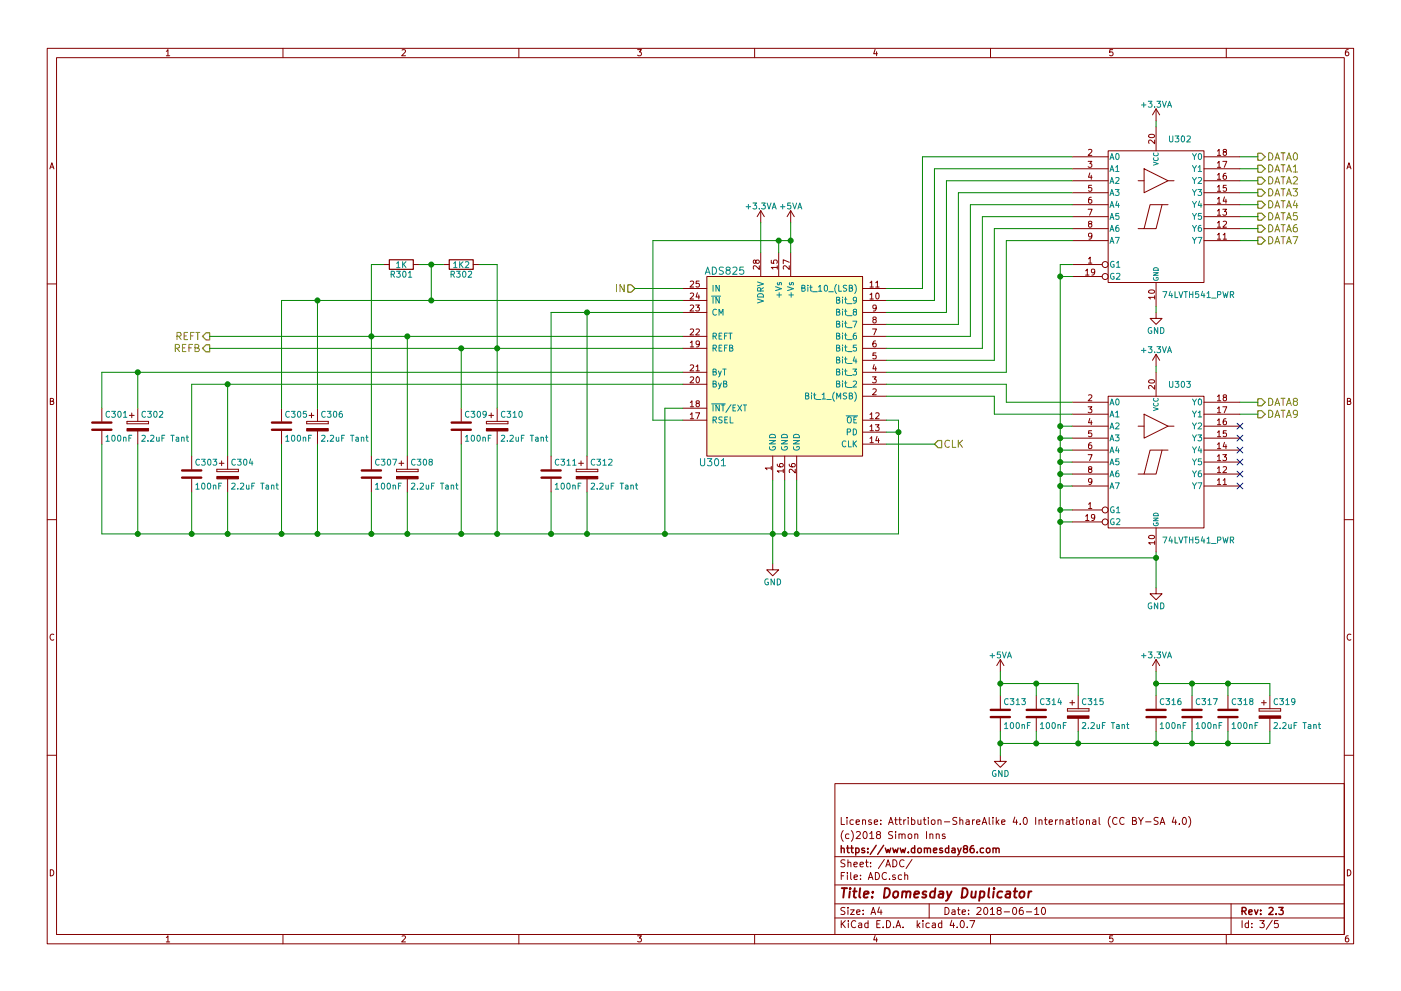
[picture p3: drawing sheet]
<svg xmlns="http://www.w3.org/2000/svg" width="297mm" height="210mm" viewBox="0 0 297 210" stroke-linecap="round" stroke-linejoin="round" font-family="sans-serif">
<g fill="none" stroke="#840000" stroke-width=".21">
<path d="M10 10.3h277v189.9h-277zM12 12.2h273v186.1h-273zM35.3 10.9l.3-.4v1.3M35.3 11.8h.7M60 10.3v1.9M85.2 10.6l.5-.1 .3 .4-.8 .9h.8M110 10.3v1.9M135.2 10.5h.8l-.4 .5 .3 .1 .1 .2-.1 .4-.2 .1-.5-.1M160 10.3v1.9M185.5 10.5l-.3 .9h.8M185.9 11v.8M210 10.3v1.9"/>
<path d="M235.9 10.5h-.6v.6h.6l.1 .5-.3 .2-.4-.1M260 10.3v1.9M285.9 10.5l-.4 .1-.2 .2-.1 .8 .3 .2 .4-.1 .1-.4-.1-.2-.4-.1-.3 .3M10.6 35.8l.4-1.3 .4 1.3M10.7 35.5h.6M227.3 38.3h7.6M227.3 33.3h7.6M227.3 35.8h7.6M230.7 34.2h.8l-.4 .5 .3 .1v.6l-.1 .1-.6-.1M230.8 31.8l.5-.1 .2 .3-.8 1h.8M231.1 36.7l-.3 .9h.7M231.4 37.2v.8"/>
<path d="M231.4 39.3h-.6v.6h.6v.6l-.1 .1-.5-.1M234.9 32h20.4v27.9h-20.4zM241.3 38.3h1.3M242.6 35.8l5 2.5-5 2.6zM243.6 28.7a.76 .76 0 0 1 1.2 .2 .74 .74 0 0 1-1.3-.1zM244.8 29.7v.8l-.9-.8-.4 .2 .1 .5M245.1 23.1v2.5M245.1 26.9v5.1M245.1 23.1l-.8 1.3M245.1 23.1l.8 1.3M247.6 38.3h1.3M255.3 38.3h7.6"/>
<path d="M255.3 33.3h7.6M255.3 35.8h7.6M258.1 39.7l.4-.4v1.3M258.1 37.1l.4-.3v1.2M258.1 34.6l.4-.4v1.3M258.1 32l.4-.3v1.3M258.1 38h.7M258.1 35.5h.7M258.1 33h.7M259.3 34.2h.8l-.5 1.3M259.6 32.2l-.3-.2 .1-.3 .6 .1v.3l-.6 .2-.1 .2 .1 .3 .2 .2h.2l.2-.3v-.3l-.2-.2M259.9 36.8h-.3l-.2 .3-.1 .7 .3 .2 .4-.1-.1-.6h-.3l-.3 .2"/>
<path d="M260 39.3h-.6l-.1 .6h.7v.6l-.2 .1-.5-.1M285.6 35.8l.4-1.3 .4 1.3M285.7 35.5h.6M81.3 56.1h1.2M87.6 56.1h1.3M94 56.1h1.2M100.3 56.1h1.3M146.4 59.7l.4-.1 .3 .4-.8 .9h.8M148.2 59.6h-.6v.6h.6v.6l-.1 .1-.5-.1M149.9 58.7h33v38.1h-33zM160.2 55.4l.3-.2h.4l.1 .2-.1 .4-.4 .1-.2-.1-.2-.6h-.3v.6l.2 .1 .2-.3M161 56.4v.8l-.9-.8-.4 .2 .1 .5"/>
<path d="M161.3 44.7v2.5M161.3 53.6v5.1M161.3 44.7l-.8 1.3M161.3 44.7l.8 1.3M163.5 55.2v.6l.6 .1v-.7h.6l.1 .2-.1 .5M164.8 56.7h-1.3l.4 .4M164.8 56.4v.7M165.1 53.6v5.1M167.3 56.4v.8l-.9-.8-.3 .2 .1 .5M167.3 55.6l-1.2-.5v.9M167.6 44.7v2.5M167.6 53.6v5.1"/>
<path d="M167.6 44.7l-.7 1.3M167.6 44.7l.8 1.3M184.5 60l.3-.4v1.3M185.7 60l.3-.4v1.3M227.3 56.1h6.4M227.3 40.9h7.6M227.3 43.4h7.6M227.3 46h7.6M227.3 48.5h7.6M227.3 51h7.6M227.3 58.7h6.4M230.2 57.4l.3-.3v1.3"/>
<path d="M230.2 58.4h.7M230.7 44.4h.8l-.5 1.3M230.8 54.9l.3-.3v1.2M230.8 55.8h.7M231 47.5l-.2-.3v-.2h.6v.3l-.5 .2-.1 .2v.4l.2 .1h.3l.2-.3-.1-.3-.1-.1M231.4 41.9h-.4l-.2 .3v.7l.2 .2 .4-.1v-.6l-.4-.1-.2 .3M231.5 50l-.2 .3-.4-.1-.1-.6 .5-.1 .2 .2-.1 .7-.3 .3h-.2M232.1 57.6l-.2 .3-.4-.1-.1-.6 .5-.1 .2 .2v.8l-.4 .3h-.2M245.1 59.9v5.1M246.4 43.4l-1.3 5.1h-2.5M247.6 43.4h-3.8l-1.2 5.1h-1.3M255.3 40.9h7.6"/>
<path d="M255.3 43.4h7.6M255.3 46h7.6M255.3 48.5h7.6M255.3 51h7.6M258.1 49.8l.4-.3v1.2M258.1 47.3l.4-.4v1.3M258.1 44.7l.4-.3v1.3M258.1 42.2l.4-.3v1.2M258.1 50.7h.7M258.1 48.2h.7M258.1 45.7h.7M258.1 43.1h.7"/>
<path d="M258.1 40.6h.7M259.3 44.4h.7l-.4 .5 .4 .1v.5l-.2 .2-.5-.2M259.3 49.8l.4-.3v1.2M259.3 47l.5-.1 .2 .4-.7 .9h.7M259.3 50.7h.7M259.6 41.8l-.3 .9h.8M259.9 42.3v.8M10 60.2h2M144.8 79h5.1M144.8 73.9h5.1M144.8 71.4h5.1M144.8 66.3h5.1"/>
<path d="M144.8 63.7h5.1M144.8 61.2h5.1M146.4 77.5l.4-.1 .3 .4-.8 .9h.8M146.4 69.9l.4-.1 .3 .3-.8 1h.8M146.4 64.8l.4-.1 .3 .4-.8 .9h.8M146.4 62.3l.4-.1 .3 .3-.8 .9h.8M146.4 72.7l.3-.4v1.3M146.4 73.6h.7M147.5 64.7h.8l-.4 .5 .3 .1v.6l-.1 .1-.6-.1M147.6 77.8l.3-.4v1.3M147.6 69.9l.5-.1 .2 .3-.8 1h.8M147.6 78.7h.7"/>
<path d="M147.9 62.1l-.3 .9h.7M148.2 62.6v.8M148.3 72.9l-.2 .2-.4-.1-.1-.6 .5-.1 .2 .3-.1 .7-.3 .3h-.2M182.9 79h5.1M182.9 76.4h5.1M182.9 73.9h5.1M182.9 71.4h5.1M182.9 68.8h5.1M182.9 66.3h5.1M182.9 63.7h5.1M182.9 61.2h5.1M184.5 62.5l.3-.3v1.2"/>
<path d="M184.5 63.4h.7M184.5 60.9h.7M185 80h.8l-.5 .4 .4 .1v.6l-.2 .1-.5-.1M185 69.8h.8l-.5 1.3M185.3 67.8l-.2-.2v-.2h.6v.3l-.5 .1-.1 .2v.4l.2 .1h.2l.3-.2-.1-.4-.2-.1M185.3 77.3l-.2 1h.7M185.6 72.3l-.3 .1-.2 .2v.7l.2 .3 .4-.1-.1-.6-.3-.1-.2 .2M185.6 77.8v.9M185.7 60.9h.7M185.7 74.9h-.6v.6h.6v.5l-.2 .1-.4-.1M185.8 65.2l-.3 .3-.3-.1-.1-.6 .4-.1 .3 .2-.1 .8-.3 .3h-.2M185.8 62.3l.2-.1a.67 .67 0 0 1 .4 .6 .67 .67 0 0 1-.4 .6l-.3-.4z"/>
<path d="M243.6 61.7a.76 .76 0 0 1 1.2 .2 .74 .74 0 0 1-1.3-.1zM244.8 63.1h-1.3l.4 .3M244.8 62.7v.7M245.1 66.3v1.3h1.3l-1.3 1.2-1.3-1.2h1.3M245.1 75.2v2.5M245.1 79v5.1M245.1 75.2l-.8 1.2M245.1 75.2l.8 1.2M285 60.2h2M10.7 85.1h.5l.1-.5-.6-.1v1.3h.5l.2-.4-.3-.3M21.6 86.6v2.8M21.6 91.4v2.8"/>
<path d="M26.9 89.4v.5zM26.9 89.9h4.6zM26.9 89.4h4.6zM27.4 88.1h1M27.9 87.6v1M29.2 86.6v2.8M29.2 91.4v2.8M31.5 89.4v.5zM40.6 96.8v2.8M46 99.6v.5zM46 99.6h4.5zM46.5 98.3h1"/>
<path d="M47 97.8v1M48.3 96.8v2.8M50.5 99.6v.5zM59.7 86.6v2.8M59.7 91.4v2.8M65 89.4v.5zM65 89.9h4.6zM65 89.4h4.6zM65.5 88.1h1M66 87.6v1M67.3 86.6v2.8M67.3 91.4v2.8"/>
<path d="M69.6 89.4v.5zM78.7 96.8v2.8M84.1 99.6v.5zM84.1 99.6h4.5zM84.6 98.3h1M85.1 97.8v1M86.4 96.8v2.8M88.6 99.6v.5zM97.8 86.6v2.8M97.8 91.4v2.8M103.1 89.4v.5zM103.1 89.9h4.6z"/>
<path d="M103.1 89.4h4.6zM103.6 88.1h1M104.1 87.6v1M105.4 86.6v2.8M105.4 91.4v2.8M107.7 89.4v.5zM116.8 96.8v2.8M122.2 99.6v.5zM122.2 99.6h4.5zM122.7 98.3h1M123.2 97.8v1M124.5 96.8v2.8"/>
<path d="M126.7 99.6v.5zM144.8 81.5h5.1M144.8 89.1h5.1M144.8 86.6h5.1M146.4 80.1l.4-.1 .3 .3-.8 .9h.8M146.4 87.9l.3-.3v1.2M146.4 85.4l.3-.4v1.3M146.4 88.8h.7M146.4 86.3h.7M147.5 87.6h.8l-.5 1.2M147.7 80.1l.2-.1a.67 .67 0 0 1 .4 .6 .67 .67 0 0 1-.4 .6l-.3-.5zM147.8 85.6l-.2-.3v-.2h.6v.3l-.5 .2-.1 .2v.4l.2 .1h.3l.2-.3-.1-.3-.1-.1"/>
<path d="M163.5 99.3h-1.2l.3 .4M163.5 99v.7M163.8 96.8v5M164.8 98.5v.3l.3 .2 .7 .1 .3-.3-.2-.4-.6 .1v.3l.2 .3M166.1 99.9h-1.3l.4 .4M166.1 99.6v.7M166.4 96.8v5M167.3 98.5l.1 .3 .2 .2 .8 .1 .2-.3-.1-.4-.6 .1-.1 .3 .2 .3M168.6 99.6v.7l-.9-.7-.4 .2 .1 .5M168.9 96.8v5M182.9 84.1h5.1M182.9 81.5h5.1"/>
<path d="M182.9 89.1h5.1M182.9 91.7h5.1M182.9 94.2h5.1M184.5 87.9l.3-.3v1.2M184.5 90.5l.3-.4v1.3M184.5 93l.3-.3v1.2M184.5 88.8h.7M184.5 91.4h.7M184.5 93.9h.7M185.1 82.6l.4-.1 .3 .3-.8 1h.8M185.6 90.1h.8l-.4 .5 .3 .1v.6l-.1 .1-.6-.1M185.7 87.7l.5-.1 .2 .3-.8 .9h.8"/>
<path d="M186 92.6l-.3 .9h.7M186.3 93.1v.8M227.3 90.4h7.6M227.3 85.3h7.6M227.3 87.9h7.6M227.3 93h7.6M227.3 95.5h7.6M227.3 98h7.6M230.7 86.3h.8l-.4 .5 .3 .1v.5l-.1 .2-.6-.2M230.7 96.5h.8l-.5 1.2M230.8 83.9l.5-.1 .2 .3-.8 .9h.8M231 99.5l-.2-.2v-.2h.6v.3l-.5 .2-.1 .2v.3l.2 .2h.3l.2-.3-.1-.3-.1-.2"/>
<path d="M231.1 88.8l-.3 .9h.7M231.4 93.9l-.4 .1-.2 .2v.7l.2 .3 .4-.1v-.6l-.4-.1-.2 .2M231.4 89.2v.9M231.4 91.4h-.6v.6h.6v.5l-.1 .2-.5-.2M234.9 84.1h20.4v27.9h-20.4zM241.3 90.4h1.3M242.6 87.9l5 2.5-5 2.6zM243.6 80.7a.76 .76 0 0 1 1.2 .3 .74 .74 0 0 1-1.3-.1zM244.8 81.8v.8l-.9-.8-.4 .2 .1 .5M246.4 95.5l-1.3 5.1h-2.5M247.6 95.5h-3.8l-1.2 5.1h-1.3M247.6 90.4h1.3"/>
<path d="M255.3 90.4h7.6M255.3 85.3h7.6M255.3 87.9h7.6M255.3 93h7.6M255.3 95.5h7.6M255.3 98h7.6M258.1 99.4l.4-.4v1.3M258.1 96.8l.4-.3v1.2M258.1 94.3l.4-.4v1.3M258.1 91.7l.4-.3v1.3M258.1 89.2l.4-.4v1.3M258.1 86.7l.4-.4v1.3"/>
<path d="M258.1 84.1l.4-.3v1.2M258.1 97.7h.7M258.1 95.2h.7M258.1 92.7h.7M258.1 90.1h.7M258.1 87.6h.7M258.1 85h.7M259.3 96.5h.7l-.4 .4 .4 .1v.6l-.2 .1-.5-.1M259.3 86.3h.8l-.5 1.3M259.3 99.1l.5-.1 .2 .4-.7 .9h.7M259.6 84.3l-.3-.2 .1-.3 .6 .1v.3l-.6 .1-.1 .3 .1 .3 .2 .1h.2l.2-.2v-.4l-.2-.1M259.6 93.8l-.3 1h.8"/>
<path d="M259.9 88.8l-.3 .1-.2 .2-.1 .8 .3 .2 .4-.1-.1-.6-.3-.1-.3 .3M259.9 94.3v.9M260 91.4h-.6l-.1 .6h.7v.5l-.2 .2-.5-.2M285.7 85.1h.5l.1-.5-.6-.1v1.3h.5l.2-.4-.3-.3M10 110.3h2M40.6 101.6v2.8M46 100.1h4.5zM48.3 101.6v2.8M78.7 101.6v2.8M84.1 100.1h4.5zM86.4 101.6v2.8M116.8 101.6v2.8"/>
<path d="M122.2 100.1h4.5zM124.5 101.6v2.8M163.8 119.6v1.3h1.3l-1.3 1.3-1.2-1.3h1.2M227.3 108.2h6.4M227.3 100.6h7.6M227.3 103.1h7.6M227.3 110.7h6.4M230.2 109.5l.3-.3v1.2M230.2 110.4h.7M230.8 107l.3-.4v1.3M230.8 107.9h.7M231.5 102.1l-.2 .2h-.4l-.1-.7 .5-.1 .2 .3-.1 .7-.3 .3h-.2"/>
<path d="M232.1 109.7l-.2 .3-.4-.1-.1-.6 .5-.1 .2 .2v.7l-.4 .3h-.2M243.6 113.8a.76 .76 0 0 1 1.2 .2 .74 .74 0 0 1-1.3-.1zM244.8 115.2h-1.3l.4 .3M244.8 114.8v.7M245.1 112v5.1M255.3 100.6h7.6M255.3 103.1h7.6M258.1 101.9l.4-.4v1.3M258.1 102.8h.7M258.1 100.3h.7M259.3 101.9l.4-.4v1.3M259.3 102.8h.7"/>
<path d="M285 110.3h2M11.4 134.6a.58 .58 0 0 0-.8 .6 .58 .58 0 0 0 .8 .5M212.1 139.9v2.6M212.1 139.9l-.8 1.3M212.1 139.9l.8 1.3M245.1 124.7v1.3h1.3l-1.3 1.2-1.3-1.2h1.3M245.1 139.9v2.6M245.1 139.9l-.8 1.3M245.1 139.9l.8 1.3M286.4 134.6a.58 .58 0 0 0-.8 .6 .58 .58 0 0 0 .8 .5M212.1 147.6v2.8M212.1 152.4v2.8"/>
<path d="M219.7 147.6v2.8M219.7 152.4v2.8M226.3 150.4v.5zM226.3 150.9h4.6zM226.3 150.4h4.6zM226.8 149.1h1M227.3 148.6v1M228.6 147.6v2.8M228.6 152.4v2.8M230.9 150.4v.5zM245.1 147.6v2.8M245.1 152.4v2.8"/>
<path d="M252.7 147.6v2.8M252.7 152.4v2.8M260.3 147.6v2.8M260.3 152.4v2.8M267 150.4v.5zM267 150.9h4.5zM267 150.4h4.5zM267.5 149.1h1M268 148.6v1M269.2 147.6v2.8M269.2 152.4v2.8M271.5 150.4v.5z"/>
<path d="M10 160.2h2M177 166.3h108v32h-108zM178.4 173.4v1.5h.7M178.8 176.2a1.71 1.71 0 0 0 0 2.3M179.6 173.4v.2M179.6 173.9v1M180 177l-.4-.1-.3 .3v.6l.3 .1 .4-.1M180.5 176.2a1.71 1.71 0 0 1 0 2.3M180.9 174l-.4-.1-.3 .3 .1 .6 .2 .1 .4-.1M181.5 174.4l.7-.1v-.3l-.5-.1-.2 .2 .1 .7h.6M181.6 176.6l.5-.2 .3 .5-.9 1h.9M182.9 174.1l.2-.2 .4 .1v.9"/>
<path d="M182.9 173.9v1M183.1 176.6l.2-.2a.8 .8 0 0 1 .6 .8 .8 .8 0 0 1-.6 .7l-.3-.5zM184.4 176.9l.4-.5v1.5M184.4 177.9h.9M184.7 174l-.3-.1-.3 .2 .1 .3 .5 .1v.3h-.6M185.4 174.4l.7-.1-.1-.3-.4-.1-.2 .2v.7h.6M186.1 177.1l-.3-.3 .1-.2 .2-.2 .4 .1 .2 .2-.1 .2-.5 .2-.3 .3v.2l.3 .3h.3l.3-.3v-.2l-.3-.3M186.7 174.8v.1M186.7 174v.1M188.4 174.9l.5-1.5 .5 1.5M188.5 174.5h.7M189.3 176.5l-.6-.1-.3 .3 .1 .3 .7 .4v.4l-.2 .1-.6-.1"/>
<path d="M189.7 173.9h.5M189.9 176.4v.2M189.9 173.4v1.3l.3 .2M189.9 176.9v1M190.6 173.9h.5M190.6 177.1l.2-.2 .4 .1v.9M190.6 176.9v1M190.8 173.4v1.3l.3 .2M191.2 177.1l.3-.2 .3 .1 .1 .9M191.6 173.9v1M192 173.9l-.4 .3M192.6 173.4v.2"/>
<path d="M192.6 173.9v1M192.6 177.1l.2-.2 .4 .2 .1 .5-.1 .2-.4 .1-.2-.1zM193.3 174l.4-.1 .3 .3-.1 .6h-.6M193.3 173.4v1.5M194 177.1l.2-.2 .3 .1 .1 .9M194 176.9v1M194.6 173.9l.1 .9 .3 .1 .2-.1M195.2 173.9v1M195.8 173.9h.5M196 173.4v1.3l.3 .2M196.4 176.4v1.5M196.8 173.4v.2"/>
<path d="M196.8 173.9v1M197.2 177.1l.2-.2 .3 .1 .1 .9M197.2 176.9v1M197.5 174.1l.2-.2 .5 .2v.5l-.1 .2-.4 .1-.2-.1zM198.5 177.1l.2-.2 .4 .1v.9M198.5 176.9v1M198.9 174.1l.2-.2 .4 .1v.9M198.9 173.9v1M200.2 174.4h1.2M200.4 177l-.4-.1-.2 .2v.3l.6 .1v.3h-.6M202.9 173.5l-.6-.1-.3 .3 .1 .3 .7 .4v.4l-.2 .1-.6-.1M203.5 174.1l.2-.2 .4 .1v.9"/>
<path d="M203.5 173.4v1.5M204.9 174h.5l.1 .9M205.5 174.3l-.7 .3 .2 .3 .5-.1M206.2 173.9v1M206.6 173.9l-.4 .3M207.1 174.4l.7-.1-.1-.3-.4-.1-.2 .2v.7h.6M208.2 174.9l.5-1.5 .5 1.5M208.4 174.5h.7M209.7 173.4v1.3l.2 .2M210.5 173.4v.2M210.5 173.9v1M211.2 173.4v1.5"/>
<path d="M211.4 174.4l.4 .5M211.8 173.9l-.6 .6M212.1 160.3v1.2h1.3l-1.3 1.3-1.3-1.3h1.3M212.4 174.4l.7-.1-.1-.3-.4-.1-.2 .2v.7h.6M215.2 173.3l-.4 1.1h.9M215.5 173.9v1M216.3 174.8v.1M217.1 173.6l.2-.2a.8 .8 0 0 1 .5 .8 .8 .8 0 0 1-.5 .7l-.4-.5zM219.6 173.4v1.5M220.3 174.1l.2-.2 .4 .1v.9M220.3 173.9v1M221.4 173.9h.6"/>
<path d="M221.6 173.4v1.3l.4 .2M222.4 174.4l.7-.1v-.3l-.4-.1-.3 .2 .1 .7h.6M223.8 173.9v1M224.2 173.9l-.4 .3M224.7 174.1l.2-.2 .4 .1 .1 .9M224.7 173.9v1M226.1 174h.6v.9M226.7 174.3l-.7 .3 .2 .3 .5-.1M227.2 173.9h.6M227.4 173.4v1.3l.4 .2M228.3 173.4v.2M228.3 173.9v1"/>
<path d="M229 174.1l.2-.2 .4 .2 .1 .5-.1 .2-.4 .1-.2-.1zM230.4 174.1l.2-.2 .3 .1 .1 .9M230.4 173.9v1M231.7 174h.6v.9M232.3 174.3l-.7 .3 .3 .3 .4-.1M233 173.4v1.3l.2 .2M235.4 173.2a1.71 1.71 0 0 0 0 2.3M236.8 173.6a.71 .71 0 0 0-1 .5 .71 .71 0 0 0 .8 .8l.2-.1M238.3 173.6a.71 .71 0 0 0-1 .5 .71 .71 0 0 0 .7 .8l.3-.1M240.1 174.1l.7-.1v-.4l-.2-.2h-.5v1.5h.6l.2-.1 .1-.4-.4-.3M241.4 173.4l.5 .8 .5-.8M241.9 174.2v.7"/>
<path d="M242.9 174.4h1.1M245.5 173.5l-.5-.1-.3 .3 .1 .3 .7 .4v.4l-.2 .1-.6-.1M246 174.9l.5-1.5 .5 1.5M246.1 174.5h.7M248.9 173.3l-.4 1.1h1M249.3 173.9v1M250 174.8v.1M250.8 173.6l.2-.2a.8 .8 0 0 1 .6 .8 .8 .8 0 0 1-.6 .7l-.3-.5zM252 173.2a1.71 1.71 0 0 1 0 2.3M285 160.2h2M10.7 184.5a.65 .65 0 0 1 .7 .7 .65 .65 0 0 1-.7 .6zM35.3 198.9l.3-.4v1.3"/>
<path d="M35.3 199.8h.7M60 198.3v1.9M85.2 198.6l.5-.1 .3 .4-.8 .9h.8M110 198.3v1.9M135.2 198.5h.8l-.4 .5 .3 .1 .1 .2-.1 .4-.2 .1-.5-.1M160 198.3v1.9M177 194.8h108M177 191.8h108M177 187.8h108M177 181.8h108M178.4 195.3v1.5M178.4 185.8h.5"/>
<path d="M178.6 196l.6 .8M179.1 185.1h-.7v1.5M179.1 192.6l-.5-.1-.3 .3 .1 .3 .7 .4v.4l-.2 .1-.6-.1M179.1 182.5l-.5-.1-.3 .3 .1 .3 .7 .4v.4l-.2 .1-.6-.1M179.2 195.3l-.8 .9M179.7 185.1v.2M179.7 185.6v1M179.8 192.5v.2M179.8 183.1l.2-.2 .4 .1v.9M179.8 182.4v1.5M179.8 193v1M179.9 195.3v.2"/>
<path d="M179.9 195.8v1M180.3 193h.8l-.8 1h.8M180.4 185.1v1.3l.2 .2M181.1 183.4l.7-.1-.1-.3-.4-.1-.2 .2v.7h.6M181.1 186.1l.7-.1-.1-.3-.4-.1-.2 .2 .1 .7h.5M181.4 195.5a.71 .71 0 0 0-1 .5 .71 .71 0 0 0 .8 .8l.2-.1M181.6 193.5l.7-.1v-.3l-.4-.1-.3 .2 .1 .7h.6M182.1 195.9h.6v.9M182.3 183.4l.8-.1-.1-.3-.4-.1-.3 .2 .1 .7h.6M182.4 186.5v.1M182.4 185.7v.1M182.7 196.2l-.7 .3 .2 .3 .5-.1"/>
<path d="M183 193.9v.1M183 193.1v.1M183.5 182.9h.6M183.7 182.4v1.3l.4 .2M184 195.9l-.4-.1-.3 .3 .1 .6 .2 .1 .4-.1M184 195.3v1.5M184.1 186.6l.5-1.5 .5 1.5M184.2 186.2h.7M184.6 183.8v.1M184.6 183v.1M184.7 194l.4-1.5 .5 1.5M184.8 193.6h.7"/>
<path d="M185.5 198.5l-.3 .9h.8M185.6 185.1a.76 .76 0 0 1 .9 .8 .76 .76 0 0 1-.9 .7zM185.9 199v.8M185.9 196h.5M186.4 192.5l-.3 1h.9M186.6 195.3h-.7v1.5h.7M186.8 193v1M187.2 196.7v.1M187.5 182.3l-1.3 2M187.8 183.9l.5-1.5 .5 1.5M187.9 183.5h.7M188 195.3a.76 .76 0 0 1 .8 .8 .76 .76 0 0 1-.8 .7z"/>
<path d="M188 185.3a.71 .71 0 0 0-1 .5 .71 .71 0 0 0 .7 .8l.3-.1M188.6 186.5v.1M189.3 182.4a.76 .76 0 0 1 .9 .8 .76 .76 0 0 1-.9 .7zM189.5 196.7v.1M189.8 185.7l-.3-.1-.3 .2 .1 .2 .5 .2v.3h-.6M190 196.8l.4-1.5 .6 1.5M190.1 196.4h.7M191.2 185.7l-.5-.1-.3 .3 .1 .6 .2 .1 .5-.1M191.5 196.7v.1M191.7 182.6a.71 .71 0 0 0-1 .5 .71 .71 0 0 0 .7 .8l.3-.1M191.8 185.7l.2-.1 .4 .1 .1 .9M191.8 185.1v1.5"/>
<path d="M193.4 182.3l-1.3 2M194.5 195.3v1.5M194.6 196.3l.4 .5M195 195.8l-.5 .6M195.7 195.3v.2M195.7 195.8v1M197 191.8v3M197 195.9l-.4-.1-.3 .3 .1 .6 .2 .1 .4-.1M197.7 195.9h.6v.9M198.3 196.2l-.7 .3 .2 .3 .5-.1M199.7 195.9l-.5-.1-.2 .3v.6l.2 .1 .5-.1M199.7 195.3v1.5"/>
<path d="M200.4 192.5a.76 .76 0 0 1 .8 .8 .76 .76 0 0 1-.8 .7zM201.8 195.2l-.4 1.1h1M201.9 193.1h.5l.1 .9M202.2 195.8v1M202.5 193.4l-.7 .3 .2 .3 .5-.1M202.9 196.7v.1M203 193h.6M203.2 192.5v1.3l.4 .2M203.8 195.4l.1-.1a.8 .8 0 0 1 .6 .8 .8 .8 0 0 1-.6 .7 .97 .97 0 0 1-.1-1.4zM204 193.5l.7-.1-.1-.3-.4-.1-.2 .2 .1 .7h.5M205.1 196.7v.1M205.4 193.9v.1"/>
<path d="M205.4 193.1v.1M205.6 195.3h1.1l-.7 1.5M207.1 192.7l.6-.2 .3 .5-.9 1h.9M208.7 192.7l.2-.2a.8 .8 0 0 1 .5 .8 .8 .8 0 0 1-.5 .7l-.3-.5zM210 193l.4-.5v1.5M210 194h.8M210 198.3v1.9M211.7 193.2l-.3-.3 .1-.2 .2-.2 .4 .1 .2 .2-.1 .2-.5 .2-.3 .3v.2l.3 .3h.3l.3-.3v-.2l-.3-.3M212.9 193.5h1.1M214.8 192.7l.2-.2a.8 .8 0 0 1 .6 .8 .8 .8 0 0 1-.6 .7l-.3-.5zM216.8 192.5l-.4 .1a1.11 1.11 0 0 0-.1 1.3l.4 .1 .2-.1 .1-.5-.3-.3-.4 .1-.2 .2M217.6 193.5h1.1"/>
<path d="M219.4 193l.4-.5v1.5M219.4 194h.8M221 192.7l.2-.2a.8 .8 0 0 1 .5 .8 .8 .8 0 0 1-.5 .7l-.4-.5zM235.9 198.5h-.6v.7l.6-.1 .1 .5-.3 .2-.4-.1M260 198.3v1.9M261 191.8v6.5M263.3 195.3v1.5M264.7 195.9l-.4-.1-.3 .3 .1 .6 .2 .1 .4-.1M264.7 195.3v1.5M265.4 196.7v.1M265.4 195.9v.1M267.1 195.3h.9l-.5 .6 .5 .1v.7l-.2 .1-.7-.1"/>
<path d="M269.7 195.2l-1.2 2M271 195.3h-.7l-.1 .7h.7l.1 .2v.5l-.2 .1-.6-.1M285.7 184.5a.65 .65 0 0 1 .7 .7 .65 .65 0 0 1-.7 .6zM285.9 198.5l-.4 .1-.2 .3-.1 .7 .3 .2 .4-.1 .1-.4-.1-.2-.4-.1-.3 .3"/>
<circle cx="234.3" cy="58.7" r=".63"/>
<circle cx="234.3" cy="56.1" r=".63"/>
<circle cx="234.3" cy="108.2" r=".63"/>
<circle cx="234.3" cy="110.7" r=".63"/>
</g>
<g fill="none" stroke="#840000" stroke-width=".3">
<path d="M178.4 179.4v1.5M179.5 179.9h.6M179.7 179.4v1.3l.4 .2M180.4 179.9h.5M180.6 179.4v1.3l.3 .2M181.4 179.9v1.5M185.8 179.3l-1.3 2M187.4 179.3l-1.3 2M187.7 179.9l.3 1 .3-.7 .3 .7 .2-1M189.3 179.9l.3 1 .3-.7 .2 .7 .3-1M190.9 179.9l.3 1 .2-.7 .3 .7 .3-1M193.9 179.4v1.5"/>
<path d="M196 179.9v1M201.1 179.4v1.5M203 179.9l.4 1M203.8 179.9l-.5 1.4-.3 .1M206.4 179.4l-.4 .1a1.11 1.11 0 0 0-.2 1.3l.5 .1 .2-.1 .1-.5-.3-.3-.5 .1-.1 .2M210.5 179.9v1M178.4 180.1l.2-.2 .3 .1 .1 .9M181.4 180l.5-.1 .2 .3-.1 .6h-.6M183.3 180l-.4-.1-.2 .2 .1 .3 .5 .1v.3h-.6M184 180.8v.1M184 180v.1M192.6 180.8v.1"/>
<path d="M193.9 180l-.4-.1-.3 .3 .1 .6 .2 .1 .4-.1M194.6 180.1l.2-.2 .5 .2 .1 .5-.2 .2-.4 .1-.2-.1zM196 180.1l.2-.2 .4 .1v.9M196.6 180.1l.2-.2 .4 .1 .1 .9M197.9 180.4l.7-.1v-.3l-.5-.1-.2 .2 .1 .7h.6M199.8 180l-.4-.1-.2 .2 .1 .3 .5 .1v.3h-.6M201.1 180l-.4-.1-.3 .3 .1 .6 .2 .1 .4-.1M201.9 180h.5l.1 .9M202.5 180.3l-.7 .3 .2 .3 .5-.1M204.5 180.1l-.2-.3v-.2l.2-.2 .5 .1 .1 .2v.2l-.6 .2-.2 .3v.2l.2 .3h.4l.2-.3v-.2l-.2-.3M207.2 180.8v.1M208.5 180l-.4-.1-.3 .3 .1 .6 .2 .1 .4-.1"/>
<path d="M209.2 180.1l.2-.2 .4 .2 .1 .5-.1 .2-.4 .1-.2-.1zM210.5 180.1l.2-.2 .4 .1 .1 .9M211.2 180.1l.2-.2 .4 .1v.9M263.3 193.3l.8-.1 .1-.2-.1-.3-.2-.2h-.6v1.5M263.7 193.3l.5 .7M264.8 193.5l.7-.1-.1-.3-.4-.1-.2 .2v.7h.6M266 193l.3 1 .4-1M267.3 193.9v.1M267.3 193.1v.1M269.1 192.7l.5-.2 .3 .5-.9 1h.9M270.6 193.9v.1M271.1 192.5h1l-.5 .6 .4 .1v.7l-.2 .1-.7-.1"/>
</g>
<g fill="none" stroke="#840000" stroke-width=".41">
<path d="M178.5 188.4h1.1M179 188.4l-.2 2M180.2 189.1l-.2 1.3M180.3 188.4l-.1 .2 .2-.1-.1-.1-.1 .2M180.9 189.1h.7M181.2 188.4l-.2 1.8 .1 .1 .4 .1M182.4 188.4l-.2 1.8 .2 .2M183.2 189.8l.9-.2v-.4l-.6-.1-.3 .3v.9h.7M184.9 190.3v.1M185.1 189.2l-.1 .2-.1-.1 .2-.1-.1 .2M187.6 188.4a1 1 0 0 1 1.1 .8 1 1 0 0 1-.5 1.1l-.8 .1zM189.5 189.3l.3-.2 .6 .2v.8l-.4 .3-.6-.1z"/>
<path d="M191.3 189.3l.3-.2 .5 .1v1.2M191.4 189.1l-.2 1.3M192.2 189.4a.52 .52 0 0 1 .8-.2l-.1 1.2M193.9 189.8l.9-.2v-.4h-.8l-.2 1 .3 .2 .5-.1M196.4 189.2l-.5-.1-.3 .4 .3 .3 .4 .1 .1 .3-.1 .1h-.8M198.2 189.2l-.2-.1a.67 .67 0 0 0-.8 .4v.8l.3 .1 .6-.1M198.3 188.4l-.2 2M199.2 189.2h.7v1.2M200 189.6l-.7 .1a.4 .4 0 0 0-.3 .3 .4 .4 0 0 0 .2 .4l.7-.1M200.8 189.1l.3 1.3M201.8 189.1l-.9 1.8-.4 .2M204.1 188.4a1 1 0 0 1 1.1 .8 1 1 0 0 1-.6 1.1l-.7 .1z"/>
<path d="M206 189.1v1.2l.5 .1 .3-.1M206.9 189.1l-.1 1.3M207.8 189.2l.6-.1 .3 .2-.1 1a.67 .67 0 0 1-.9 0M207.8 189.1l-.2 2M209.7 188.4l-.2 1.8 .3 .2M210.7 189.1l-.2 1.3M210.8 188.4l-.1 .2 .2-.1-.1-.1-.1 .2M212.5 189.2l-.2-.1a.67 .67 0 0 0-.8 .4v.8l.3 .1 .6-.1M213.4 189.2h.7v1.2M214.2 189.6l-.7 .1a.4 .4 0 0 0-.3 .3 .4 .4 0 0 0 .2 .4l.7-.1M214.9 189.1h.8M215.3 188.4l-.2 1.8v.1l.4 .1"/>
<path d="M216.3 189.3l.3-.2 .6 .2-.1 .8-.4 .3-.5-.1zM218.1 189.1l-.1 1.3M218.7 189.1l-.4 .1-.2 .3"/>
</g>
<path d="M149.9 58.7h33v38.1h-33z" fill="#ffffc2" stroke="#ffffc2" stroke-width=".21"/>
<g fill="none" stroke="#008484" stroke-width=".21">
<path d="M235.3 33.9l.4-1.3 .5 1.3M235.3 36.4l.4-1.3 .5 1.3M235.3 38.9l.4-1.2 .5 1.2M235.5 33.5h.5M235.5 36h.5M235.5 38.6h.5M236.6 35.5l.3-.4v1.3M236.6 37.8l.4-.1 .3 .3-.8 .9h.8M236.6 36.4h.7M236.7 32.7l.1-.1a.67 .67 0 0 1 .5 .6 .67 .67 0 0 1-.5 .7l-.2-.5zM242 22.3h1M242.5 21.8v1"/>
<path d="M243.5 21.5h.7l-.4 .5 .4 .1v.5l-.2 .2-.5-.2M244.6 34.4l1 .3-1 .3M244.7 33.5a.44 .44 0 0 0 .4 .6 .44 .44 0 0 0 .4-.6M244.7 32.5a.44 .44 0 0 0 .4 .6 .44 .44 0 0 0 .4-.6M244.8 22.6v.2M245.3 21.5h.8l-.5 .5 .4 .1v.5l-.2 .2-.5-.2M246.5 21.5l.4 1.3 .4-1.3M247.5 22.8l.5-1.3 .4 1.3M247.7 22.4h.6M248 28.8v1.1l.2 .2h.2l.3-.2v-1.1M249.1 28.8h.8l-.4 .5 .4 .1v.6l-.2 .1-.6-.1M250.5 29l.2-.2a.67 .67 0 0 1 .5 .7 .67 .67 0 0 1-.5 .6l-.3-.5z"/>
<path d="M251.7 29l.4-.2 .3 .4-.8 .9h.8M252.8 37.7l.4 .6 .5-.6M252.8 35.1l.4 .7 .5-.7M252.8 32.6l.4 .6 .5-.6M253.2 33.2v.7M253.2 35.8v.6M253.2 38.3v.6M254.1 37.8l.4-.1 .3 .3-.8 .9h.8M254.1 35.5l.3-.4v1.3M254.1 36.4h.7M254.2 32.7l.1-.1a.67 .67 0 0 1 .5 .6 .67 .67 0 0 1-.5 .7l-.2-.5zM82.9 58.2l.6-.1 .1-.4-.7-.1v1.2"/>
<path d="M83.2 58.2l.4 .6M84.1 57.6h.8l-.5 .4 .4 .1v.6l-.2 .1-.5-.1M84.1 55.9l.4-.4v1.3M84.1 56.8h.7M85.4 55.5v1.3M85.5 57.7l.1-.1a.67 .67 0 0 1 .5 .6 .67 .67 0 0 1-.5 .6l-.2-.5zM85.5 56.1l.6 .7M86.1 55.5l-.7 .7M86.6 57.9l.3-.3v1.2M86.6 58.8h.7M95.6 58.2l.6-.1 .1-.4-.7-.1v1.2M95.9 58.2l.4 .6"/>
<path d="M96.2 55.9l.3-.4v1.3M96.2 56.8h.7M96.8 57.6h.8l-.5 .4 .4 .1v.6l-.2 .1-.5-.1M97.5 55.5v1.3M97.6 56.1l.6 .7M98.2 57.7l.1-.1a.67 .67 0 0 1 .5 .6 .67 .67 0 0 1-.5 .6l-.2-.5zM98.2 55.5l-.7 .7M98.7 55.6l.5-.1 .2 .4-.8 .9h.8M99.3 57.7l.5-.1 .2 .3-.8 .9h.8M149.5 58.2l.5-1.5 .5 1.5M149.7 57.8h.7M151 56.7a.77 .77 0 0 1 .9 .7 .77 .77 0 0 1-.9 .8z"/>
<path d="M153.4 56.7h-.6l-.3 .3 .1 .3 .7 .3v.4l-.2 .2-.6-.1M154.2 57.3l-.3-.3 .1-.2 .2-.1h.5l.1 .3-.1 .2-.6 .2-.2 .2v.3l.3 .3h.3l.3-.3v-.3l-.3-.3M155.4 56.8l.6-.1 .3 .4-1 1.1h1M157.6 56.7h-.7l-.1 .7 .2-.2 .6 .1 .1 .6-.3 .3-.6-.2M158.2 43.9h1M158.7 43.4v.9M159.6 43.1h.8l-.4 .5 .4 .1v.5l-.2 .1-.6-.1M160.6 59.8l1.3 .4-1.3 .4M161 44.2v.1M161.5 43.1h.8l-.5 .5 .4 .1v.5l-.2 .1-.5-.1M162.6 43.1l.4 1.2 .5-1.2M163.7 44.3l.4-1.2 .5 1.2"/>
<path d="M163.9 44h.5M164.9 60l-.1 .3 .2 .1h.2l.1-.4h.3v.4M165.5 43.9h.9M165.9 43.4v.9M167.4 60v.3l.1 .1h.2l.1-.4h.3v.4M167.6 43.1h-.6v.6h.6v.5l-.1 .1-.5-.1M168.1 43.1l.4 1.2 .4-1.2M169.2 44.3l.4-1.2 .4 1.2M169.3 44h.6M235.3 41.5l.4-1.3 .5 1.3M235.3 44l.4-1.3 .5 1.3M235.3 46.6l.4-1.3 .5 1.3"/>
<path d="M235.3 49.1l.4-1.3 .5 1.3M235.3 51.6l.4-1.2 .5 1.2M235.5 41.1h.5M235.5 43.6h.5M235.5 46.2h.5M235.5 48.7h.5M235.5 51.3h.5M236.2 55.5a.59 .59 0 0 0-.7 .6 .59 .59 0 0 0 .7 .5v-.4h-.2M236.2 58a.59 .59 0 0 0-.7 .6 .59 .59 0 0 0 .7 .6v-.5h-.2M236.5 40.2h.8l-.5 .5 .4 .1v.5l-.2 .2-.5-.2M236.5 50.4h.8l-.5 1.2M236.7 55.8l.4-.4v1.3"/>
<path d="M236.7 58.1l.5-.1 .2 .3-.7 1h.7M236.7 56.7h.7M236.8 42.7l-.2 .9h.7M237.1 47.8l-.3 .1-.2 .2v.7l.2 .3 .4-.1-.1-.6-.3-.1-.2 .2M237.1 43.1v.9M237.2 45.3h-.6v.6h.6v.5l-.2 .2-.4-.2M244.6 57.9h1l-1 .5h1M244.6 58.9a.45 .45 0 0 0 .5 .6 .45 .45 0 0 0 .4-.6h-.4v.1M244.6 57a.55 .55 0 0 1 .6-.2 .55 .55 0 0 1 .4 .5h-1zM252.8 50.4l.4 .6 .5-.6M252.8 47.8l.4 .7 .5-.7M252.8 45.3l.4 .6 .5-.6"/>
<path d="M252.8 42.7l.4 .7 .5-.7M252.8 40.2l.4 .7 .5-.7M253.2 40.9v.6M253.2 43.4v.6M253.2 45.9v.7M253.2 48.5v.6M253.2 51v.6M254 50.4h.8l-.5 1.2M254 40.2h.8l-.5 .5 .4 .1v.5l-.2 .2-.5-.2M254.3 42.7l-.2 .9h.7M254.6 47.8l-.3 .1-.2 .2v.7l.2 .3 .4-.1-.1-.6-.3-.1-.2 .2M254.6 43.1v.9"/>
<path d="M254.7 45.3h-.6v.6h.6v.5l-.2 .2-.4-.2M150.9 62.8h1.9M151.2 78.9l.6-.1v-.4l-.6-.1v1.3h.5l.2-.5-.3-.2M151.2 71.3h.6v-.5l-.6-.1v1.3M151.2 73.9l.6-.1v-.5l-.6-.1v1.3M151.2 60.5v1.3M151.2 63.1v1.2M151.5 71.3l.4 .7M151.5 73.9l.4 .6M151.9 65.7a.56 .56 0 0 0-.8 .5 .56 .56 0 0 0 .8 .5M152.3 78.7l.3 .9M152.5 66.9v-1.3l.4 .9 .4-.9v1.3"/>
<path d="M152.5 71.3h.4M152.5 73.8h.4M152.5 63.1v1.2l-.7-1.2v1.2M152.5 60.5v1.3l-.7-1.3v1.3M152.9 78.7l-.4 1.2-.2 .1M153.1 70.7h-.6v1.3h.6M153.1 73.2h-.6v1.3h.6M153.2 78.3h.7M153.6 78.3v1.3M153.6 71.3h.4M153.6 73.8h.4M154.2 70.7h-.6v1.3"/>
<path d="M154.2 73.2h-.6v1.3M154.5 70.7h.7M154.7 73.8l.6-.1v-.4l-.6-.1v1.3h.5l.2-.4-.3-.3M154.9 70.7v1.3M160.6 63.4l1.3 .5-1.3 .4M160.7 62.5a.69 .69 0 0 1 .7-.2 .69 .69 0 0 1 .5 .7h-1.3zM161.3 61.7l-.1-.6h-.5l-.1 .6h1.3M161.9 61l-.6 .4M164.4 60.8l1.3 .5-1.3 .4M164.7 62.6h1M165.2 62.1v1M167 60.8l1.2 .5-1.2 .4"/>
<path d="M167.3 62.6h.9M167.7 62.1v1M170 61.1l.6-.1v-.4l-.6-.1v1.3h.5l.2-.4-.3-.3M171.3 60.5v.1M171.3 60.9v.9M171.7 60.9h.5M171.9 60.5v1.1l.3 .2M172.3 61.9h1M173.5 60.9l.4-.4v1.3M173.5 61.8h.7M174.9 60.6l.1-.1a.67 .67 0 0 1 .5 .7 .67 .67 0 0 1-.5 .6l-.2-.5zM175.7 61.9h1"/>
<path d="M177.3 60.3a1.51 1.51 0 0 0 0 2M177.4 78.9l.6-.1v-.4l-.6-.1v1.3h.5l.2-.5-.3-.2M177.4 76.3l.6-.1v-.3l-.6-.1v1.2h.5l.2-.4-.3-.3M177.4 73.8l.6-.1v-.4l-.6-.1v1.3h.5l.2-.4-.3-.3M177.4 71.3l.6-.1v-.4l-.6-.1v1.3h.5l.2-.5-.3-.2M177.4 68.7l.6-.1v-.4l-.6-.1v1.3h.5l.2-.4-.3-.3M177.4 66.2l.6-.1v-.4l-.6-.1v1.3h.5l.2-.5-.3-.2M177.4 63.6l.6-.1v-.3l-.6-.1v1.2h.5l.2-.4-.3-.3M177.8 60.5v1.3h.6M178.6 78.3v.1M178.6 75.8v.1M178.6 73.2v.1"/>
<path d="M178.6 70.7v.1M178.6 68.1v.1M178.6 65.6v.1M178.6 63.1v.1M178.6 63.5v.8M178.6 66v.9M178.6 68.5v.9M178.6 71.1v.9M178.6 73.6v.9M178.6 76.2v.8M178.6 78.7v.9M179.1 78.7h.5"/>
<path d="M179.1 76.2h.5M179.1 73.6h.5M179.1 71.1h.5M179.1 68.5h.5M179.1 66h.5M179.1 63.5h.5M179.2 78.3v1.1l.4 .2M179.2 75.8v1l.4 .2M179.2 73.2v1.1l.4 .2M179.2 70.7v1l.4 .3M179.2 68.1v1.1l.4 .2M179.2 65.6v1.1l.4 .2"/>
<path d="M179.2 63.1v1l.4 .2M179.5 60.6h-.6l-.1 .4a.54 .54 0 0 1 .7 .7l-.2 .1-.5-.1M179.7 79.7h.9M179.7 77.1h.9M179.7 74.6h.9M179.7 72.1h.9M179.7 69.5h.9M179.7 67h.9M179.7 64.4h.9M180.1 61.1l.6-.1v-.4l-.6-.1v1.3h.4l.3-.4-.3-.3M180.8 78.3h.8l-.4 .5 .4 .1v.5l-.2 .2-.6-.2M180.8 68.1h.9l-.6 1.3"/>
<path d="M181.1 66.1l-.2-.2 .1-.2h.6v.3l-.6 .2-.1 .2v.3l.2 .2h.3l.2-.3v-.3l-.2-.2M181.2 75.7l-.3 .9h.8M181.2 60.3a1.51 1.51 0 0 1 0 2M181.5 70.7h-.4l-.2 .3v.7l.2 .3 .5-.2-.1-.6h-.4l-.2 .2M181.5 76.2v.8M181.6 73.2h-.7v.6h.7v.6l-.2 .1-.5-.1M181.6 63.6l-.2 .2h-.4l-.1-.6 .5-.1 .2 .2v.7l-.3 .3h-.3M242 74.3h1M242.5 73.9v.9M243.5 73.6h.7l-.4 .4 .4 .1v.6l-.2 .1-.5-.1M244.1 69.5a.59 .59 0 0 0-.7 .6 .59 .59 0 0 0 .7 .6l.1-.5h-.2M244.8 74.7v.1"/>
<path d="M245.3 73.6h.8l-.5 .4 .4 .1v.6l-.2 .1-.5-.1M245.5 69.5v1.3l-.7-1.3v1.3M246.1 69.5a.64 .64 0 0 1 .7 .6 .64 .64 0 0 1-.7 .7zM246.5 73.6l.4 1.2 .4-1.2M246.6 61.9h.8l-.5 1.2M247.5 74.8l.5-1.2 .4 1.2M247.7 74.4h.6M248.1 61.8l-.2 .9h.7M248.4 62.3v.8M249.1 61.9v1.2h.6M250 61.9l.4 1.2 .4-1.2M251.1 61.9h.7"/>
<path d="M251.4 61.9v1.2M252.2 61.9v1.2M252.2 62.5h.7M252.9 61.9v1.2M254.1 61.9h-.6v.6h.6v.5l-.2 .1-.4-.1M255 61.8l-.3 .9h.7M255.3 62.3v.8M255.9 62.2l.4-.3v1.2M255.9 63.1h.7M256.9 63.2h.9M258.1 62.5h.6l.1-.5-.7-.1v1.2M259.3 61.9l.3 1.2 .2-.9 .3 .9 .3-1.2"/>
<path d="M260.9 62.5h.6v-.5l-.6-.1v1.2M261.2 62.5l.4 .6M22.5 92.7l.3-.4v1.3M22.5 93.6h.7M23.2 87.4a.56 .56 0 0 0-.7 .5 .56 .56 0 0 0 .7 .5M23.7 87.3h.8l-.5 .5 .4 .1v.5l-.2 .1-.5-.1M23.8 92.5l.2-.2a.67 .67 0 0 1 .4 .7 .67 .67 0 0 1-.4 .6l-.3-.5zM25 92.5l.2-.2a.67 .67 0 0 1 .4 .7 .67 .67 0 0 1-.4 .6l-.3-.5zM25.1 87.4l.1-.1a.67 .67 0 0 1 .5 .6 .67 .67 0 0 1-.5 .6l-.2-.4zM26.2 87.6l.3-.3v1.2M26.2 92.9l.2-.1h.3v.8M26.2 88.5h.7"/>
<path d="M26.2 92.8v.8M27.3 92.9h.5M27.9 92.3h-.6v1.3M30.1 92.5l.5-.2 .2 .4-.8 .9h.8M30.9 87.4a.56 .56 0 0 0-.8 .5 .56 .56 0 0 0 .8 .5M31.3 87.3h.8l-.5 .5 .4 .1v.5l-.1 .1-.6-.1M31.4 93.5v.1M31.9 92.5l.5-.2 .2 .4-.7 .9h.7M32.7 87.4l.2-.1a.67 .67 0 0 1 .4 .6 .67 .67 0 0 1-.4 .6l-.3-.4zM33.2 92.8v.7l.4 .1 .1-.1M33.7 92.8v.8M33.8 87.4l.5-.1 .2 .3-.8 .9h.8"/>
<path d="M34.3 92.9h.5M35 92.3h-.7v1.3M36.2 92.3h.7M36.6 92.3v1.3M37.4 92.8h.4l.1 .8M37.9 93.1l-.6 .2 .2 .3 .4-.1M38.5 92.9l.2-.1h.3v.8M38.5 92.8v.8M39.5 92.8h.5M39.6 92.3v1.1l.4 .2M42.3 97.5a.56 .56 0 0 0-.8 .6 .56 .56 0 0 0 .8 .5M42.7 97.4h.8l-.4 .5 .4 .1v.6l-.2 .1-.6-.1"/>
<path d="M44.1 97.5l.2-.1a.67 .67 0 0 1 .4 .7 .67 .67 0 0 1-.4 .6l-.3-.5zM45.2 97.4h.7l-.4 .5 .4 .1v.6l-.2 .1-.5-.1M49.9 97.5a.56 .56 0 0 0-.8 .6 .56 .56 0 0 0 .8 .5M50.3 97.4h.8l-.4 .5 .4 .1v.6l-.2 .1-.6-.1M51.7 97.5l.2-.1a.67 .67 0 0 1 .5 .7 .67 .67 0 0 1-.5 .6l-.3-.5zM53.1 97.4l-.2 .9h.7M53.4 97.8v.9M60.6 92.7l.3-.4v1.3M60.6 93.6h.7M61.3 87.4a.56 .56 0 0 0-.7 .5 .56 .56 0 0 0 .7 .5M61.8 87.3h.8l-.5 .5 .4 .1v.5l-.2 .1-.5-.1M61.9 92.5l.2-.2a.67 .67 0 0 1 .4 .7 .67 .67 0 0 1-.4 .6l-.3-.5z"/>
<path d="M63.1 92.5l.2-.2a.67 .67 0 0 1 .4 .7 .67 .67 0 0 1-.4 .6l-.3-.5zM63.2 87.4l.1-.1a.67 .67 0 0 1 .5 .6 .67 .67 0 0 1-.5 .6l-.2-.4zM64.3 92.9l.2-.1h.3v.8M64.3 92.8v.8M64.9 87.3h-.6v.6h.6v.5l-.1 .1-.5-.1M65.4 92.9h.5M66 92.3h-.6v1.3M68.2 92.5l.5-.2 .2 .4-.8 .9h.8M69 87.4a.56 .56 0 0 0-.8 .5 .56 .56 0 0 0 .8 .5M69.4 87.3h.8l-.5 .5 .4 .1v.5l-.1 .1-.6-.1M69.5 93.5v.1M70 92.5l.5-.2 .2 .4-.7 .9h.7"/>
<path d="M70.8 87.4l.2-.1a.67 .67 0 0 1 .4 .6 .67 .67 0 0 1-.4 .6l-.3-.4zM71.3 92.8v.7l.4 .1 .1-.1M71.8 92.8v.8M72.4 92.9h.5M72.5 87.3h-.4l-.1 .3-.1 .7 .2 .2 .5-.1-.1-.6h-.4l-.2 .2M73.1 92.3h-.7v1.3M74.3 92.3h.7M74.7 92.3v1.3M75.5 92.8h.4l.1 .8M76 93.1l-.6 .2 .2 .3 .4-.1M76.6 92.9l.2-.1h.3v.8M76.6 92.8v.8"/>
<path d="M77.6 92.8h.5M77.7 92.3v1.1l.4 .2M80.4 97.5a.56 .56 0 0 0-.8 .6 .56 .56 0 0 0 .8 .5M80.8 97.4h.8l-.4 .5 .4 .1v.6l-.2 .1-.6-.1M82.2 97.5l.2-.1a.67 .67 0 0 1 .4 .7 .67 .67 0 0 1-.4 .6l-.3-.5zM83.3 97.4h.8l-.5 1.3M88 97.5a.56 .56 0 0 0-.8 .6 .56 .56 0 0 0 .8 .5M88.4 97.4h.8l-.4 .5 .4 .1v.6l-.2 .1-.6-.1M89.8 97.5l.2-.1a.67 .67 0 0 1 .5 .7 .67 .67 0 0 1-.5 .6l-.3-.5zM91.2 98l-.2-.3v-.2h.6v.3l-.5 .2-.1 .2v.4l.2 .1h.2l.3-.3-.1-.3-.2-.1M98.7 92.7l.3-.4v1.3M98.7 93.6h.7"/>
<path d="M99.4 87.4a.56 .56 0 0 0-.7 .5 .56 .56 0 0 0 .7 .5M99.9 87.3h.8l-.5 .5 .4 .1v.5l-.2 .1-.5-.1M100 92.5l.2-.2a.67 .67 0 0 1 .4 .7 .67 .67 0 0 1-.4 .6l-.3-.5zM101.2 92.5l.2-.2a.67 .67 0 0 1 .4 .7 .67 .67 0 0 1-.4 .6l-.3-.5zM101.3 87.4l.1-.1a.67 .67 0 0 1 .5 .6 .67 .67 0 0 1-.5 .6l-.2-.4zM102.4 92.9l.2-.1h.3v.8M102.4 92.8v.8M103.1 87.8l-.2 .3-.4-.1-.1-.6 .5-.1 .2 .2-.1 .7-.3 .3h-.2M103.5 92.9h.5M104.1 92.3h-.6v1.3M106.3 92.5l.5-.2 .2 .4-.8 .9h.8M107.1 87.4a.56 .56 0 0 0-.8 .5 .56 .56 0 0 0 .8 .5"/>
<path d="M107.5 87.3h.8l-.5 .5 .4 .1v.5l-.1 .1-.6-.1M107.6 93.5v.1M108.1 92.5l.5-.2 .2 .4-.7 .9h.7M108.8 87.6l.3-.3v1.2M108.8 88.5h.7M109.4 92.8v.7l.4 .1 .1-.1M109.9 92.8v.8M110.1 87.4l.2-.1a.67 .67 0 0 1 .4 .6 .67 .67 0 0 1-.4 .6l-.3-.4zM110.5 92.9h.5M111.2 92.3h-.7v1.3M112.4 92.3h.7M112.8 92.3v1.3"/>
<path d="M113.6 92.8h.4l.1 .8M114.1 93.1l-.6 .2 .2 .3 .4-.1M114.7 92.9l.2-.1h.3v.8M114.7 92.8v.8M115.7 92.8h.5M115.8 92.3v1.1l.4 .2M118.5 97.5a.56 .56 0 0 0-.8 .6 .56 .56 0 0 0 .8 .5M118.9 97.4h.8l-.4 .5 .4 .1v.6l-.2 .1-.6-.1M120.2 97.8l.4-.4v1.3M120.2 98.7h.7M121.4 97.8l.4-.4v1.3M121.4 98.7h.7"/>
<path d="M126.1 97.5a.56 .56 0 0 0-.8 .6 .56 .56 0 0 0 .8 .5M126.5 97.4h.8l-.4 .5 .4 .1v.6l-.2 .1-.6-.1M127.8 97.8l.4-.4v1.3M127.8 98.7h.7M129.1 97.5l.4-.1 .3 .4-.8 .9h.8M148.5 97.3v1.2l.3 .3h.3l.3-.3v-1.2M150 97.3h.9l-.5 .6 .5 .3v.5l-.3 .1-.6-.1M150.9 85.7h2.9M151.2 81.4l.6-.1v-.4l-.6-.1v1.3h.5l.2-.4-.3-.3M151.2 89.1l.6-.1v-.4l-.6-.1v1.2M151.2 85.9v1.3M151.5 89.1l.4 .6"/>
<path d="M151.6 97.5l.3-.2a.81 .81 0 0 1 .5 .8 .81 .81 0 0 1-.5 .7l-.3-.1-.1-.5zM152.3 81.2l.3 .9M152.5 85.9v1.3l-.7-1.3v1.3M152.9 81.2l-.4 1.2-.2 .1M152.9 97.7l.5-.4v1.5M152.9 85.9h.7M152.9 98.8h.9M153.1 88.5h-.6v.4a.54 .54 0 0 1 .6 .7l-.2 .1h-.5M153.3 85.9v1.3M153.4 81.4l.6-.1v-.4l-.6-.1v1.3h.5l.2-.4-.3-.3M153.7 89h.4M154.3 88.5h-.6v1.2h.6"/>
<path d="M154.8 88.5v1.2h.6M155 85.8l-1.1 1.7M155.4 86.5h.4M156 85.9h-.6v1.3h.6M156.4 85.9l.9 1.3M157.3 85.9l-.9 1.3M157.6 85.9h.7M157.9 85.9v1.3M163.1 93.5h1.3l-1.3 .7h1.3M163.2 94.8a.59 .59 0 0 0 .6 .7 .59 .59 0 0 0 .5-.7l-.4-.1v.3M163.2 92.4a.69 .69 0 0 1 .8-.2 .69 .69 0 0 1 .4 .7h-1.3zM165.7 93.5h1.3l-1.3 .7h1.3"/>
<path d="M165.7 94.8a.59 .59 0 0 0 .6 .7 .59 .59 0 0 0 .6-.7l-.5-.1v.3M165.7 92.4a.69 .69 0 0 1 .8-.2 .69 .69 0 0 1 .5 .7h-1.3zM168.2 93.5h1.3l-1.3 .7h1.3M168.3 94.8a.59 .59 0 0 0 .5 .7 .59 .59 0 0 0 .6-.7l-.5-.1v.3M168.3 92.4a.69 .69 0 0 1 .8-.2 .69 .69 0 0 1 .4 .7h-1.3zM170.8 84l.6-.1v-.4l-.6-.1v1.3h.5l.2-.5-.3-.2M172.1 83.4v.1M172.1 83.8v.9M172.5 83.8h.5M172.7 83.4v1l.3 .3M173.1 84.8h1M174.3 83.7l.4-.3v1.3"/>
<path d="M174.3 84.7h.7M175.3 84.8h1M176.9 83.2a1.51 1.51 0 0 0 0 1.9M177.4 81.4l.6-.1v-.4l-.6-.1v1.3h.5l.2-.4-.3-.3M177.4 84.7v-1.3l.4 .9 .4-.9v1.3M178.6 80.8v.1M178.6 81.2v.9M179.1 81.2h.5M179.2 80.8v1.1l.4 .2M179.3 93.6a.56 .56 0 0 0-.7 .6 .56 .56 0 0 0 .7 .5M179.4 88.2h2.5M179.5 83.4h-.6l-.1 .5a.54 .54 0 0 1 .7 .6l-.2 .2-.5-.1"/>
<path d="M179.6 91.7l.6-.1 .1-.5-.7-.1v1.3M179.7 82.2h.9M179.7 88.6l.2-.1h.4l.2 .8a.42 .42 0 0 1-.2 .4 .42 .42 0 0 1-.5 0l-.1-.4zM179.9 93.5v1.3h.6M180.1 84l.6-.1v-.4l-.6-.1v1.3h.4l.3-.5-.3-.2M180.9 80.9l.5-.1 .2 .4-.8 .9h.8M180.9 91a.64 .64 0 0 1 .7 .6 .64 .64 0 0 1-.7 .7zM180.9 93.5v1.3M181 89h.5M181.1 94.1l.5 .7M181.2 83.2a1.51 1.51 0 0 1 0 1.9M181.6 93.5l-.7 .8"/>
<path d="M181.6 88.5h-.6v1.2h.6M235.3 85.9l.4-1.2 .5 1.2M235.3 88.5l.4-1.3 .5 1.3M235.3 91l.4-1.3 .5 1.3M235.3 93.5l.4-1.2 .5 1.2M235.3 96.1l.4-1.3 .5 1.3M235.3 98.6l.4-1.2 .5 1.2M235.5 85.5h.5M235.5 88.1h.5M235.5 90.6h.5M235.5 93.2h.5M235.5 95.7h.5"/>
<path d="M235.5 98.2h.5M236.5 92.3h.8l-.5 .5 .4 .1v.5l-.2 .1-.5-.1M236.6 87.5l.3-.3v1.3M236.6 89.8l.4-.1 .3 .4-.8 .9h.8M236.6 88.5h.7M236.7 84.8l.1-.1a.67 .67 0 0 1 .5 .6 .67 .67 0 0 1-.5 .6l-.2-.5zM236.8 94.7l-.2 1h.7M237.1 99.9h-.3l-.2 .3v.7l.2 .3 .4-.2-.1-.6h-.3l-.2 .2M237.1 95.2v.9M237.2 97.4h-.6v.5h.6v.6l-.2 .1-.4-.1M244.6 86.5l1 .3-1 .3M244.7 85.5a.44 .44 0 0 0 .4 .7 .44 .44 0 0 0 .4-.7"/>
<path d="M244.7 84.5a.44 .44 0 0 0 .4 .6 .44 .44 0 0 0 .4-.6M248 80.9v1l.2 .3h.2l.3-.3v-1M249.1 80.9h.8l-.4 .5 .4 .1v.6l-.2 .1-.6-.1M250.5 81l.2-.1a.67 .67 0 0 1 .5 .7 .67 .67 0 0 1-.5 .6l-.3-.5zM251.6 80.9h.8l-.5 .5 .4 .1v.6l-.2 .1-.5-.1M252.8 99.9l.4 .7 .5-.7M252.8 97.4l.4 .6 .5-.6M252.8 94.8l.4 .7 .5-.7M252.8 92.3l.4 .6 .5-.6M252.8 89.7l.4 .7 .5-.7M252.8 87.2l.4 .7 .5-.7M252.8 84.7l.4 .6 .5-.6"/>
<path d="M253.2 85.3v.6M253.2 87.9v.6M253.2 90.4v.6M253.2 92.9v.6M253.2 95.5v.6M253.2 98v.6M254 92.3h.8l-.5 .5 .4 .1v.5l-.2 .1-.5-.1M254.1 89.8l.4-.1 .3 .4-.8 .9h.8M254.1 87.5l.3-.3v1.3M254.1 88.5h.7M254.2 84.8l.1-.1a.67 .67 0 0 1 .5 .6 .67 .67 0 0 1-.5 .6l-.2-.5zM254.3 94.7l-.2 1h.7"/>
<path d="M254.6 99.9h-.3l-.2 .3v.7l.2 .3 .4-.2-.1-.6h-.3l-.2 .2M254.6 95.2v.9M254.7 97.4h-.6v.5h.6v.6l-.2 .1-.4-.1M41.5 102.9l.4-.4v1.3M41.5 103.8h.7M42.8 102.6l.2-.1a.67 .67 0 0 1 .5 .6 .67 .67 0 0 1-.5 .7l-.3-.5zM44.1 102.6l.1-.1a.67 .67 0 0 1 .5 .6 .67 .67 0 0 1-.5 .7l-.2-.5zM45.2 103l.2-.1 .3 .1 .1 .8M45.2 102.9v.9M46.4 103.1h.4M47 102.5h-.6v1.3M49.1 102.6l.5-.1 .3 .4-.8 .9h.8"/>
<path d="M50.4 103.7v.1M51 102.6l.5-.1 .2 .4-.8 .9h.8M52.2 102.9l.1 .8 .3 .1 .2-.1M52.8 102.9v.9M53.4 103.1h.4M54 102.5h-.6v1.3M55.3 102.5h.7M55.6 102.5v1.3M56.4 103h.5v.8M56.9 103.2l-.5 .3 .1 .3 .4-.1M57.6 103l.1-.1 .3 .1 .1 .8M57.6 102.9v.9"/>
<path d="M58.5 102.9h.5M58.7 102.5v1.1l.3 .2M79.6 102.9l.4-.4v1.3M79.6 103.8h.7M80.9 102.6l.2-.1a.67 .67 0 0 1 .5 .6 .67 .67 0 0 1-.5 .7l-.3-.5zM82.2 102.6l.1-.1a.67 .67 0 0 1 .5 .6 .67 .67 0 0 1-.5 .7l-.2-.5zM83.3 103l.2-.1 .3 .1 .1 .8M83.3 102.9v.9M84.5 103.1h.4M85.1 102.5h-.6v1.3M87.2 102.6l.5-.1 .3 .4-.8 .9h.8M88.5 103.7v.1"/>
<path d="M89.1 102.6l.5-.1 .2 .4-.8 .9h.8M90.3 102.9l.1 .8 .3 .1 .2-.1M90.9 102.9v.9M91.5 103.1h.4M92.1 102.5h-.6v1.3M93.4 102.5h.7M93.7 102.5v1.3M94.5 103h.5v.8M95 103.2l-.5 .3 .1 .3 .4-.1M95.7 103l.1-.1 .3 .1 .1 .8M95.7 102.9v.9M96.6 102.9h.5"/>
<path d="M96.8 102.5v1.1l.3 .2M117.7 102.9l.4-.4v1.3M117.7 103.8h.7M119 102.6l.2-.1a.67 .67 0 0 1 .5 .6 .67 .67 0 0 1-.5 .7l-.3-.5zM120.3 102.6l.1-.1a.67 .67 0 0 1 .5 .6 .67 .67 0 0 1-.5 .7l-.2-.5zM121.4 103l.2-.1 .3 .1 .1 .8M121.4 102.9v.9M122.6 103.1h.4M123.2 102.5h-.6v1.3M125.3 102.6l.5-.1 .3 .4-.8 .9h.8M126.6 103.7v.1M127.2 102.6l.5-.1 .2 .4-.8 .9h.8"/>
<path d="M128.4 102.9l.1 .8 .3 .1 .2-.1M129 102.9v.9M129.6 103.1h.4M130.2 102.5h-.6v1.3M131.5 102.5h.7M131.8 102.5v1.3M132.6 103h.5v.8M133.1 103.2l-.5 .3 .1 .3 .4-.1M133.8 103l.1-.1 .3 .1 .1 .8M133.8 102.9v.9M134.7 102.9h.5M134.9 102.5v1.1l.3 .2"/>
<path d="M235.3 101.2l.4-1.3 .5 1.3M235.3 103.7l.4-1.3 .5 1.3M235.5 100.8h.5M235.5 103.3h.5M236.2 107.6a.59 .59 0 0 0-.7 .5 .59 .59 0 0 0 .7 .6v-.5h-.2M236.2 110.1a.59 .59 0 0 0-.7 .6 .59 .59 0 0 0 .7 .5v-.4h-.2M236.5 102.4h.8l-.5 1.3M236.7 107.9l.4-.4v1.3M236.7 110.2l.5-.1 .2 .3-.7 .9h.7M236.7 108.8h.7M244.6 109.9h1l-1 .6h1M244.6 111a.45 .45 0 0 0 .5 .6 .45 .45 0 0 0 .4-.7h-.4v.2"/>
<path d="M244.7 108.9a.53 .53 0 0 1 .6 0 .53 .53 0 0 1 .3 .5h-1zM246.6 113.9h.8l-.5 1.3M248.1 113.9l-.2 .9h.7M248.4 114.3v.9M249.1 113.9v1.3h.6M250 113.9l.4 1.3 .4-1.3M251.1 113.9h.7M251.4 113.9v1.3M252.2 113.9v1.3M252.2 114.5h.7M252.8 102.4l.4 .7 .5-.7M252.9 113.9v1.3"/>
<path d="M253.2 100.6v.6M253.2 103.1v.6M254 102.4h.8l-.5 1.3M254.1 113.9h-.6v.6h.6v.6l-.2 .1-.4-.1M255 113.9l-.3 .9h.7M255.3 114.3v.9M255.9 114.3l.4-.4v1.3M255.9 115.2h.7M256.9 115.3h.9M258.1 114.6l.6-.1 .1-.5-.7-.1v1.3M259.3 113.9l.3 1.3 .2-.9 .3 .9 .3-1.3M260.9 114.6l.6-.1v-.5l-.6-.1v1.3"/>
<path d="M261.2 114.6l.4 .6M162.9 122.9a.59 .59 0 0 0-.8 .6 .59 .59 0 0 0 .8 .5v-.5h-.2M164.2 122.8v1.3l-.7-1.3v1.3M164.8 122.8a.64 .64 0 0 1 .7 .7 .64 .64 0 0 1-.7 .6zM209.9 139.1h1M210.4 138.6v1M212.1 138.3h-.6l-.1 .6h.7v.6l-.2 .1-.5-.1M212.5 138.3l.4 1.3 .5-1.3M213.6 139.6l.4-1.3 .5 1.3M213.7 139.2h.6M242 139.1h1M242.5 138.6v1"/>
<path d="M243.5 138.3h.7l-.4 .5 .4 .1v.6l-.2 .1-.5-.1M244.1 128a.59 .59 0 0 0-.7 .5 .59 .59 0 0 0 .7 .6l.1-.5h-.2M244.8 139.5v.1M245.3 138.3h.8l-.5 .5 .4 .1v.6l-.2 .1-.5-.1M245.5 127.9v1.3l-.7-1.3v1.3M246.1 127.9a.64 .64 0 0 1 .7 .6 .64 .64 0 0 1-.7 .7zM246.5 138.3l.4 1.3 .4-1.3M247.5 139.6l.5-1.3 .4 1.3M247.7 139.2h.6M213 153.7l.3-.4v1.3M213 154.6h.7M213.7 148.3a.56 .56 0 0 0-.7 .6 .56 .56 0 0 0 .7 .5"/>
<path d="M214.2 148.2h.8l-.5 .5 .4 .1v.6l-.2 .1-.5-.1M214.3 153.4l.2-.1a.67 .67 0 0 1 .4 .6 .67 .67 0 0 1-.4 .7l-.3-.5zM215.5 148.6l.3-.4v1.3M215.5 149.5h.7M215.5 153.4l.2-.1a.67 .67 0 0 1 .4 .6 .67 .67 0 0 1-.4 .7l-.3-.5zM216.6 148.2h.8l-.4 .5 .3 .1v.6l-.1 .1-.6-.1M216.7 153.8l.2-.1 .3 .1v.8M216.7 153.7v.9M217.8 153.9h.5M218.4 153.3h-.6v1.3M220.6 153.7l.4-.4v1.3M220.6 154.6h.7"/>
<path d="M221.4 148.3a.56 .56 0 0 0-.8 .6 .56 .56 0 0 0 .8 .5M221.8 148.2h.8l-.5 .5 .4 .1v.6l-.1 .1-.6-.1M221.9 153.4l.2-.1a.67 .67 0 0 1 .4 .6 .67 .67 0 0 1-.4 .7l-.3-.5zM223.1 148.6l.3-.4v1.3M223.1 149.5h.7M223.1 153.4l.2-.1a.67 .67 0 0 1 .5 .6 .67 .67 0 0 1-.5 .7l-.3-.5zM224.3 153.8l.2-.1 .3 .1v.8M224.3 153.7v.9M224.6 148.2l-.3 .9h.8M224.9 148.6v.9M225.5 153.9h.4M226.1 153.3h-.6v1.3"/>
<path d="M229.5 153.4l.5-.1 .2 .4-.8 .9h.8M230.3 148.3a.56 .56 0 0 0-.8 .6 .56 .56 0 0 0 .8 .5M230.7 148.2h.8l-.5 .5 .4 .1v.6l-.2 .1-.5-.1M230.8 154.5v.1M231.3 153.4l.5-.1 .2 .4-.8 .9h.8M232 148.6l.3-.4v1.3M232 149.5h.7M232.6 153.7v.8l.3 .1 .2-.1M233.1 153.7v.9M233.7 153.9h.5M233.9 148.2h-.7v.6h.7v.6l-.2 .1-.5-.1M234.3 153.3h-.6v1.3"/>
<path d="M235.6 153.3h.7M236 153.3v1.3M236.8 153.8h.4l.1 .8M237.3 154l-.6 .3 .2 .3 .4-.1M237.9 153.8l.2-.1 .3 .1v.8M237.9 153.7v.9M238.9 153.7h.4M239 153.3v1.1l.3 .2M246 153.7l.4-.4v1.3M246 154.6h.7M246.8 148.3a.56 .56 0 0 0-.8 .6 .56 .56 0 0 0 .8 .5M247.2 148.2h.8l-.5 .5 .4 .1v.6l-.1 .1-.6-.1"/>
<path d="M247.3 153.4l.2-.1a.67 .67 0 0 1 .4 .6 .67 .67 0 0 1-.4 .7l-.3-.5zM248.5 148.6l.3-.4v1.3M248.5 149.5h.7M248.5 153.4l.2-.1a.67 .67 0 0 1 .5 .6 .67 .67 0 0 1-.5 .7l-.3-.5zM249.7 153.8l.2-.1 .3 .1v.8M249.7 153.7v.9M250.3 148.2l-.4 .1-.1 .2-.1 .7 .2 .3 .5-.1-.1-.6-.4-.1-.2 .2M250.9 153.9h.4M251.5 153.3h-.6v1.3M253.6 153.7l.4-.4v1.3M253.6 154.6h.7M254.4 148.3a.56 .56 0 0 0-.8 .6 .56 .56 0 0 0 .8 .5"/>
<path d="M254.8 148.2h.8l-.4 .5 .3 .1v.6l-.1 .1-.6-.1M254.9 153.4l.2-.1a.67 .67 0 0 1 .5 .6 .67 .67 0 0 1-.5 .7l-.3-.5zM256.1 148.6l.4-.4v1.3M256.1 149.5h.7M256.2 153.4l.1-.1a.67 .67 0 0 1 .5 .6 .67 .67 0 0 1-.5 .7l-.2-.5zM257.3 148.2h.8l-.5 1.3M257.3 153.8l.2-.1 .3 .1 .1 .8M257.3 153.7v.9M258.5 153.9h.4M259.1 153.3h-.6v1.3M261.2 153.7l.4-.4v1.3M261.2 154.6h.8"/>
<path d="M262 148.3a.56 .56 0 0 0-.8 .6 .56 .56 0 0 0 .8 .5M262.4 148.2h.8l-.4 .5 .4 .1v.6l-.2 .1-.6-.1M262.6 153.4l.1-.1a.67 .67 0 0 1 .5 .6 .67 .67 0 0 1-.5 .7l-.2-.5zM263.7 148.6l.4-.4v1.3M263.7 149.5h.7M263.8 153.4l.2-.1a.67 .67 0 0 1 .4 .6 .67 .67 0 0 1-.4 .7l-.3-.5zM264.9 153.8l.2-.1 .3 .1 .1 .8M264.9 153.7v.9M265.2 148.8l-.3-.3 .1-.2h.6v.3l-.6 .2-.1 .2 .1 .4 .2 .1h.2l.3-.3-.1-.3-.2-.1M266.1 153.9h.4M266.7 153.3h-.6v1.3M270.1 153.4l.5-.1 .2 .4-.7 .9h.7"/>
<path d="M270.9 148.3a.56 .56 0 0 0-.8 .6 .56 .56 0 0 0 .8 .5M271.3 148.2h.8l-.4 .5 .4 .1v.6l-.2 .1-.6-.1M271.4 154.5v.1M272 153.4l.4-.1 .3 .4-.8 .9h.8M272.6 148.6l.4-.4v1.3M272.6 149.5h.7M273.2 153.7l.1 .8 .3 .1 .2-.1M273.8 153.7v.9M274.4 153.9h.4M274.5 148.8l-.2 .2-.4-.1v-.6l.4-.1 .2 .3v.7l-.3 .3h-.3M275 153.3h-.6v1.3M276.3 153.3h.7"/>
<path d="M276.6 153.3v1.3M277.4 153.8h.5v.8M277.9 154l-.6 .3 .2 .3 .4-.1M278.5 153.8l.2-.1 .3 .1 .1 .8M278.5 153.7v.9M279.5 153.7h.5M279.7 153.3v1.1l.3 .2M211.1 163.5a.59 .59 0 0 0-.7 .6 .59 .59 0 0 0 .7 .6l.1-.5h-.3M212.4 163.5v1.2l-.7-1.2v1.2M213.1 163.5a.64 .64 0 0 1 .7 .6 .64 .64 0 0 1-.7 .6z"/>
</g>
<g fill="none" stroke="#848400" stroke-width=".21">
<path d="M269 32.4a.77 .77 0 0 1 .9 .8 .77 .77 0 0 1-.9 .8zM269 35a.77 .77 0 0 1 .9 .7 .77 .77 0 0 1-.9 .8zM269 37.5a.77 .77 0 0 1 .9 .8 .77 .77 0 0 1-.9 .7zM270.3 34l.5-1.6 .5 1.6M270.3 36.5l.5-1.5 .5 1.5M270.3 39l.5-1.5 .5 1.5M270.4 33.5h.8M270.4 36.1h.8M270.4 38.6h.8M271.6 32.4h.9M271.6 35h.9M271.6 37.5h.9"/>
<path d="M272 32.4v1.6M272 35v1.5M272 37.5v1.5M272.8 34l.5-1.6 .5 1.6M272.8 36.5l.5-1.5 .5 1.5M272.8 39l.5-1.5 .5 1.5M272.9 33.5h.7M272.9 36.1h.7M272.9 38.6h.7M274.2 35.4l.5-.4v1.5M274.2 37.7l.6-.2 .3 .4-1 1.1h1M274.2 36.5h.9"/>
<path d="M274.3 32.6l.3-.2a.81 .81 0 0 1 .5 .8 .81 .81 0 0 1-.5 .8l-.3-.2-.1-.4zM269 40.1a.77 .77 0 0 1 .9 .7 .77 .77 0 0 1-.9 .8zM269 42.6a.77 .77 0 0 1 .9 .8 .77 .77 0 0 1-.9 .7zM269 45.1a.77 .77 0 0 1 .9 .8 .77 .77 0 0 1-.9 .8zM269 47.7a.77 .77 0 0 1 .9 .7 .77 .77 0 0 1-.9 .8zM269 50.2a.77 .77 0 0 1 .9 .8 .77 .77 0 0 1-.9 .7zM270.3 41.6l.5-1.5 .5 1.5M270.3 44.1l.5-1.5 .5 1.5M270.3 46.7l.5-1.6 .5 1.6M270.3 49.2l.5-1.5 .5 1.5M270.3 51.7l.5-1.5 .5 1.5M270.4 41.1h.8"/>
<path d="M270.4 43.7h.8M270.4 46.2h.8M270.4 48.8h.8M270.4 51.3h.8M271.6 40.1h.9M271.6 42.6h.9M271.6 45.1h.9M271.6 47.7h.9M271.6 50.2h.9M272 40.1v1.5M272 42.6v1.5M272 45.1v1.6"/>
<path d="M272 47.7v1.5M272 50.2v1.5M272.8 41.6l.5-1.5 .5 1.5M272.8 44.1l.5-1.5 .5 1.5M272.8 46.7l.5-1.6 .5 1.6M272.8 49.2l.5-1.5 .5 1.5M272.8 51.7l.5-1.5 .5 1.5M272.9 41.1h.7M272.9 43.7h.7M272.9 46.2h.7M272.9 48.8h.7M272.9 51.3h.7"/>
<path d="M274.1 40.1h1l-.5 .5 .5 .3-.1 .5-.2 .2-.7-.2M274.1 50.2h1.1l-.7 1.5M274.6 42.5l-.4 1.1h1M274.9 47.7h-.4a.99 .99 0 0 0 0 1.5l.5-.2 .1-.5-.3-.2h-.3l-.3 .2M274.9 43.1v1M275 45.1h-.7l-.1 .8 .2-.2 .5 .1 .2 .6-.3 .3-.6-.2M37.2 73.9l.7-.1 .1-.2v-.4l-.3-.1h-.5v1.5M37.5 71.3h.8l.1-.3-.1-.3-.2-.2h-.6v1.6M37.5 73.9l.5 .7M37.9 71.3l.5 .8M38.7 73.8h.5M39 71.3h.5"/>
<path d="M39.4 73.1h-.7v1.5h.7M39.8 70.5h-.8v1.6h.8M40.1 73.8h.5M40.4 71.3h.5M40.8 73.1h-.7v1.5M41.1 70.5h-.7v1.6M41.4 73.8l.6-.1 .2-.2-.1-.3-.7-.1v1.5h.5l.3-.2v-.3l-.3-.3M41.5 70.5h.9M41.9 70.5v1.6M130.7 60.4v1.5M132.3 60.4v1.5l-.9-1.5v1.5M201.3 93.5a.72 .72 0 0 0-1 .5 .72 .72 0 0 0 .7 .9l.3-.1"/>
<path d="M201.9 93.4v1.5h.8M203.2 93.4v1.5M203.4 94.1l.7 .8M204.1 93.4l-.9 .9M269 84.5a.77 .77 0 0 1 .9 .8 .77 .77 0 0 1-.9 .7zM269 87a.77 .77 0 0 1 .9 .8 .77 .77 0 0 1-.9 .8zM270.3 86l.5-1.5 .5 1.5M270.3 88.6l.5-1.6 .5 1.6M270.4 85.6h.8M270.4 88.1h.8M271.6 84.5h.9M271.6 87h.9"/>
<path d="M272 84.5v1.5M272 87v1.6M272.8 86l.5-1.5 .5 1.5M272.8 88.6l.5-1.6 .5 1.6M272.9 85.6h.7M272.9 88.1h.7M274.5 85.2l-.3-.3 .1-.2 .2-.2 .4 .1 .2 .2-.1 .2-.7 .2-.1 .2v.3l.3 .3h.3l.3-.3v-.3l-.3-.2M275.1 87.7l-.3 .3h-.3l-.3-.3 .1-.5 .5-.2a.96 .96 0 0 1-.1 1.6h-.4"/>
</g>
<g fill="none" stroke="#848400" stroke-width=".25">
<path d="M266.7 32.5h.8l.7 .8-.7 .7h-.8zM266.7 35h.8l.7 .8-.7 .8h-.8zM266.7 37.6h.8l.7 .7-.7 .8h-.8zM266.7 40.1h.8l.7 .8-.7 .8h-.8zM266.7 42.7h.8l.7 .7-.7 .8h-.8zM266.7 45.2h.8l.7 .8-.7 .7h-.8zM266.7 47.7h.8l.7 .8-.7 .8h-.8zM266.7 50.3h.8l.7 .7-.7 .8h-.8zM42.9 71.4l.8-.8h.7v1.5h-.7zM43.7 73.1h.7v1.6h-.7l-.8-.8zM133.1 60.4h.8l.7 .8-.7 .8h-.8zM198.9 93.5h.7v1.5h-.7l-.8-.8z"/>
<path d="M266.7 84.6h.8l.7 .7-.7 .8h-.8zM266.7 87.1h.8l.7 .8-.7 .7h-.8z"/>
</g>
<g fill="none" stroke="#840000" stroke-width=".51">
<path d="M19.6 91.2h4M19.6 89.7h4M38.6 99.8h4.1M57.7 91.2h4M57.7 89.7h4M76.7 99.8h4.1M95.8 91.2h4M95.8 89.7h4M114.8 99.8h4.1M38.6 101.3h4.1M76.7 101.3h4.1M114.8 101.3h4.1"/>
<path d="M210.1 152.1h4M210.1 150.6h4M217.7 152.1h4M217.7 150.6h4M243.1 152.1h4M243.1 150.6h4M250.7 152.1h4.1M250.7 150.6h4.1M258.3 152.1h4.1M258.3 150.6h4.1"/>
</g>
<g fill="#840000" stroke="#840000" stroke-width=".21">
<path d="M26.9 90.9h4.6v.5h-4.6z"/>
<path d="M46 101.1h4.5v.5h-4.5z"/>
<path d="M84.1 101.1h4.5v.5h-4.5z"/>
<path d="M103.1 90.9h4.6v.5h-4.6z"/>
<path d="M226.3 151.9h4.6v.5h-4.6z"/>
<path d="M267 151.9h4.5v.5h-4.5z"/>
<path d="M122.2 101.1h4.5v.5h-4.5z"/>
<path d="M65 90.9h4.6v.5h-4.6z"/>
</g>
<path d="M262.3 100l1.2 1.2M262.3 97.4l1.2 1.2M262.3 94.9l1.2 1.2M262.3 92.3l1.2 1.3M262.3 89.8l1.2 1.2M263.5 100l-1.2 1.2M263.5 97.4l-1.2 1.2M263.5 94.9l-1.2 1.2M263.5 92.3l-1.2 1.3M263.5 89.8l-1.2 1.2M262.3 102.5l1.2 1.2M263.5 102.5l-1.2 1.2" fill="none" stroke="#000084" stroke-width=".21"/>
<g fill="none" stroke="#008400" stroke-width=".21">
<path d="M227.3 33.3h-31.7v27.9h-7.6M227.3 35.8h-29.2v27.9h-10.1M227.3 38.3h-26.6v28h-12.7M245.1 25.6v1.3M262.9 33.3h3.8M262.9 35.8h3.8M262.9 38.3h3.8M81.3 56.1h-2.6v40.7M88.9 56.1h5.1M91.4 56.1v7.6M101.6 56.1h3.8v30.5M161.3 47.2v6.4"/>
<path d="M165.1 51v2.6M167.6 51h-29.2v38.1h6.4M167.6 47.2v6.4M224.8 58.7h2.5M227.3 43.4h-21.6v28h-17.7M227.3 46h-19v27.9h-20.3M227.3 51h-13.9v28h-25.4M227.3 40.9h-24.1v27.9h-15.2M227.3 48.5h-16.5v27.9h-22.8M227.3 56.1h-2.5v62.3h20.3M262.9 51h3.8M262.9 40.9h3.8"/>
<path d="M262.9 43.4h3.8M262.9 46h3.8M262.9 48.5h3.8M29.2 79v7.6M44.4 71.4h100.4M44.4 73.9h100.4M67.3 63.7v22.9M86.4 71.4v25.4M97.8 73.9v12.7M124.5 66.3v30.5M134.6 61.2h10.2M144.8 63.7h-85.1v22.9"/>
<path d="M144.8 79h-123.2v7.6M144.8 66.3h-28v30.5M245.1 65v1.3M245.1 77.7v1.3M29.2 94.2v19.1M48.3 81.5v15.3M59.7 94.2v19.1M67.3 94.2v19.1M97.8 94.2v19.1M105.4 94.2v19.1M144.8 86.6h-3.8v26.7M144.8 81.5h-104.2v15.3"/>
<path d="M188 89.1h2.5v24.2h-168.9v-19.1M188 91.7h2.5M188 81.5h25.4v3.8h13.9M188 84.1h22.8v3.8h16.5M188 94.2h10.1M224.8 90.4h2.5M224.8 93h2.5M224.8 95.5h2.5M224.8 98h2.5M262.9 85.3h3.8M262.9 87.9h3.8M40.6 104.4v8.9"/>
<path d="M48.3 104.4v8.9M78.7 104.4v8.9M86.4 104.4v8.9M116.8 104.4v8.9M124.5 104.4v8.9M163.8 101.8v17.8M166.4 101.8v11.5M168.9 101.8v11.5M224.8 110.7h2.5M224.8 108.2h2.5M224.8 100.6h2.5M224.8 103.1h2.5"/>
<path d="M245.1 117.1v7.6M212.1 142.5v5.1M212.1 155.2v5.1M212.1 145h16.5v2.6M219.7 145v2.6M219.7 155.2v2.5M228.6 155.2v2.5M245.1 142.5v5.1M245.1 155.2v2.5M245.1 145h24.1v2.6M252.7 145v2.6M252.7 155.2v2.5"/>
<path d="M260.3 145v2.6M260.3 155.2v2.5M269.2 155.2v2.5h-57.1"/>
</g>
<g fill="#008400" stroke="#008400" stroke-width=".25">
<circle cx="167.6" cy="51" r=".51"/>
<circle cx="163.8" cy="113.3" r=".51"/>
<circle cx="166.4" cy="113.3" r=".51"/>
<circle cx="168.9" cy="113.3" r=".51"/>
<circle cx="190.5" cy="91.7" r=".51"/>
<circle cx="165.1" cy="51" r=".51"/>
<circle cx="141" cy="113.3" r=".51"/>
<circle cx="29.2" cy="79" r=".51"/>
<circle cx="48.3" cy="81.5" r=".51"/>
<circle cx="29.2" cy="113.3" r=".51"/>
<circle cx="40.6" cy="113.3" r=".51"/>
<circle cx="48.3" cy="113.3" r=".51"/>
<circle cx="212.1" cy="157.7" r=".51"/>
<circle cx="212.1" cy="145" r=".51"/>
<circle cx="219.7" cy="157.7" r=".51"/>
<circle cx="224.8" cy="108.2" r=".51"/>
<circle cx="224.8" cy="58.7" r=".51"/>
<circle cx="245.1" cy="157.7" r=".51"/>
<circle cx="245.1" cy="145" r=".51"/>
<circle cx="252.7" cy="145" r=".51"/>
<circle cx="252.7" cy="157.7" r=".51"/>
<circle cx="245.1" cy="118.4" r=".51"/>
<circle cx="224.8" cy="110.7" r=".51"/>
<circle cx="59.7" cy="113.3" r=".51"/>
<circle cx="78.7" cy="71.4" r=".51"/>
<circle cx="86.4" cy="71.4" r=".51"/>
<circle cx="97.8" cy="73.9" r=".51"/>
<circle cx="105.4" cy="73.9" r=".51"/>
<circle cx="78.7" cy="113.3" r=".51"/>
<circle cx="86.4" cy="113.3" r=".51"/>
<circle cx="97.8" cy="113.3" r=".51"/>
<circle cx="105.4" cy="113.3" r=".51"/>
<circle cx="219.7" cy="145" r=".51"/>
<circle cx="228.6" cy="157.7" r=".51"/>
<circle cx="260.3" cy="145" r=".51"/>
<circle cx="260.3" cy="157.7" r=".51"/>
<circle cx="124.5" cy="66.3" r=".51"/>
<circle cx="116.8" cy="113.3" r=".51"/>
<circle cx="124.5" cy="113.3" r=".51"/>
<circle cx="91.4" cy="63.7" r=".51"/>
<circle cx="91.4" cy="56.1" r=".51"/>
<circle cx="67.3" cy="113.3" r=".51"/>
<circle cx="67.3" cy="63.7" r=".51"/>
<circle cx="224.8" cy="90.4" r=".51"/>
<circle cx="224.8" cy="93" r=".51"/>
<circle cx="224.8" cy="95.5" r=".51"/>
<circle cx="224.8" cy="98" r=".51"/>
<circle cx="224.8" cy="100.6" r=".51"/>
<circle cx="224.8" cy="103.1" r=".51"/>
</g>
<path d="M82.5 55.1h5.1v2h-5.1zM95.2 55.1h5.1v2h-5.1z" fill="none" stroke="#840000" stroke-width=".25"/>
</svg>
